VERSION 5.4 ;
NAMESCASESENSITIVE ON ;
BUSBITCHARS "[]" ;
DIVIDERCHAR "/" ;
UNITS
  DATABASE MICRONS 2000 ;
END UNITS
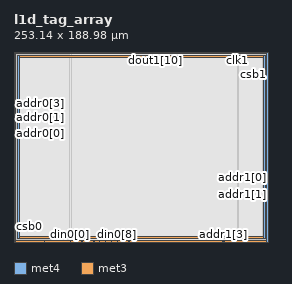
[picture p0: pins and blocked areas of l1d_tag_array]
MACRO l1d_tag_array
   CLASS BLOCK ;
   SIZE 253.14 BY 188.98 ;
   SYMMETRY X Y R90 ;
   PIN din0[0]
      DIRECTION INPUT ;
      PORT
         LAYER met4 ;
         RECT  55.92 0.0 56.3 0.38 ;
      END
   END din0[0]
   PIN din0[1]
      DIRECTION INPUT ;
      PORT
         LAYER met4 ;
         RECT  61.76 0.0 62.14 0.38 ;
      END
   END din0[1]
   PIN din0[2]
      DIRECTION INPUT ;
      PORT
         LAYER met4 ;
         RECT  67.6 0.0 67.98 0.38 ;
      END
   END din0[2]
   PIN din0[3]
      DIRECTION INPUT ;
      PORT
         LAYER met4 ;
         RECT  73.44 0.0 73.82 0.38 ;
      END
   END din0[3]
   PIN din0[4]
      DIRECTION INPUT ;
      PORT
         LAYER met4 ;
         RECT  79.28 0.0 79.66 0.38 ;
      END
   END din0[4]
   PIN din0[5]
      DIRECTION INPUT ;
      PORT
         LAYER met4 ;
         RECT  85.12 0.0 85.5 0.38 ;
      END
   END din0[5]
   PIN din0[6]
      DIRECTION INPUT ;
      PORT
         LAYER met4 ;
         RECT  90.96 0.0 91.34 0.38 ;
      END
   END din0[6]
   PIN din0[7]
      DIRECTION INPUT ;
      PORT
         LAYER met4 ;
         RECT  96.8 0.0 97.18 0.38 ;
      END
   END din0[7]
   PIN din0[8]
      DIRECTION INPUT ;
      PORT
         LAYER met4 ;
         RECT  102.64 0.0 103.02 0.38 ;
      END
   END din0[8]
   PIN din0[9]
      DIRECTION INPUT ;
      PORT
         LAYER met4 ;
         RECT  108.48 0.0 108.86 0.38 ;
      END
   END din0[9]
   PIN din0[10]
      DIRECTION INPUT ;
      PORT
         LAYER met4 ;
         RECT  114.32 0.0 114.7 0.38 ;
      END
   END din0[10]
   PIN addr0[0]
      DIRECTION INPUT ;
      PORT
         LAYER met3 ;
         RECT  0.0 107.58 0.38 107.96 ;
      END
   END addr0[0]
   PIN addr0[1]
      DIRECTION INPUT ;
      PORT
         LAYER met3 ;
         RECT  0.0 116.08 0.38 116.46 ;
      END
   END addr0[1]
   PIN addr0[2]
      DIRECTION INPUT ;
      PORT
         LAYER met3 ;
         RECT  0.0 121.72 0.38 122.1 ;
      END
   END addr0[2]
   PIN addr0[3]
      DIRECTION INPUT ;
      PORT
         LAYER met3 ;
         RECT  0.0 130.22 0.38 130.6 ;
      END
   END addr0[3]
   PIN addr0[4]
      DIRECTION INPUT ;
      PORT
         LAYER met3 ;
         RECT  0.0 136.275 0.38 136.655 ;
      END
   END addr0[4]
   PIN addr1[0]
      DIRECTION INPUT ;
      PORT
         LAYER met3 ;
         RECT  252.76 63.54 253.14 63.92 ;
      END
   END addr1[0]
   PIN addr1[1]
      DIRECTION INPUT ;
      PORT
         LAYER met3 ;
         RECT  252.76 55.04 253.14 55.42 ;
      END
   END addr1[1]
   PIN addr1[2]
      DIRECTION INPUT ;
      PORT
         LAYER met3 ;
         RECT  252.76 49.4 253.14 49.78 ;
      END
   END addr1[2]
   PIN addr1[3]
      DIRECTION INPUT ;
      PORT
         LAYER met4 ;
         RECT  207.775 0.0 208.155 0.38 ;
      END
   END addr1[3]
   PIN addr1[4]
      DIRECTION INPUT ;
      PORT
         LAYER met4 ;
         RECT  208.52 0.0 208.9 0.38 ;
      END
   END addr1[4]
   PIN csb0
      DIRECTION INPUT ;
      PORT
         LAYER met3 ;
         RECT  0.0 14.87 0.38 15.25 ;
      END
   END csb0
   PIN csb1
      DIRECTION INPUT ;
      PORT
         LAYER met3 ;
         RECT  252.76 173.73 253.14 174.11 ;
      END
   END csb1
   PIN clk0
      DIRECTION INPUT ;
      PORT
         LAYER met4 ;
         RECT  30.26 0.0 30.64 0.38 ;
      END
   END clk0
   PIN clk1
      DIRECTION INPUT ;
      PORT
         LAYER met4 ;
         RECT  222.5 188.6 222.88 188.98 ;
      END
   END clk1
   PIN dout1[0]
      DIRECTION OUTPUT ;
      PORT
         LAYER met4 ;
         RECT  109.645 188.6 110.025 188.98 ;
      END
   END dout1[0]
   PIN dout1[1]
      DIRECTION OUTPUT ;
      PORT
         LAYER met4 ;
         RECT  114.615 188.6 114.995 188.98 ;
      END
   END dout1[1]
   PIN dout1[2]
      DIRECTION OUTPUT ;
      PORT
         LAYER met4 ;
         RECT  115.885 188.6 116.265 188.98 ;
      END
   END dout1[2]
   PIN dout1[3]
      DIRECTION OUTPUT ;
      PORT
         LAYER met4 ;
         RECT  120.855 188.6 121.235 188.98 ;
      END
   END dout1[3]
   PIN dout1[4]
      DIRECTION OUTPUT ;
      PORT
         LAYER met4 ;
         RECT  122.125 188.6 122.505 188.98 ;
      END
   END dout1[4]
   PIN dout1[5]
      DIRECTION OUTPUT ;
      PORT
         LAYER met4 ;
         RECT  127.095 188.6 127.475 188.98 ;
      END
   END dout1[5]
   PIN dout1[6]
      DIRECTION OUTPUT ;
      PORT
         LAYER met4 ;
         RECT  128.365 188.6 128.745 188.98 ;
      END
   END dout1[6]
   PIN dout1[7]
      DIRECTION OUTPUT ;
      PORT
         LAYER met4 ;
         RECT  133.335 188.6 133.715 188.98 ;
      END
   END dout1[7]
   PIN dout1[8]
      DIRECTION OUTPUT ;
      PORT
         LAYER met4 ;
         RECT  134.605 188.6 134.985 188.98 ;
      END
   END dout1[8]
   PIN dout1[9]
      DIRECTION OUTPUT ;
      PORT
         LAYER met4 ;
         RECT  139.575 188.6 139.955 188.98 ;
      END
   END dout1[9]
   PIN dout1[10]
      DIRECTION OUTPUT ;
      PORT
         LAYER met4 ;
         RECT  140.845 188.6 141.225 188.98 ;
      END
   END dout1[10]
   PIN vccd1
      DIRECTION INOUT ;
      USE POWER ; 
      SHAPE ABUTMENT ; 
      PORT
         LAYER met3 ;
         RECT  0.0 187.24 253.14 188.98 ;
         LAYER met3 ;
         RECT  0.0 0.0 253.14 1.74 ;
         LAYER met4 ;
         RECT  251.4 0.0 253.14 188.98 ;
         LAYER met4 ;
         RECT  0.0 0.0 1.74 188.98 ;
      END
   END vccd1
   PIN vssd1
      DIRECTION INOUT ;
      USE GROUND ; 
      SHAPE ABUTMENT ; 
      PORT
         LAYER met3 ;
         RECT  3.48 183.76 249.66 185.5 ;
         LAYER met3 ;
         RECT  3.48 3.48 249.66 5.22 ;
         LAYER met4 ;
         RECT  3.48 3.48 5.22 185.5 ;
         LAYER met4 ;
         RECT  247.92 3.48 249.66 185.5 ;
      END
   END vssd1
   OBS
   LAYER  met1 ;
      RECT  0.62 0.62 252.52 188.36 ;
   LAYER  met2 ;
      RECT  0.62 0.62 252.52 188.36 ;
   LAYER  met3 ;
      RECT  0.98 106.98 252.52 108.56 ;
      RECT  0.62 108.56 0.98 115.48 ;
      RECT  0.62 117.06 0.98 121.12 ;
      RECT  0.62 122.7 0.98 129.62 ;
      RECT  0.62 131.2 0.98 135.675 ;
      RECT  0.98 62.94 252.16 64.52 ;
      RECT  0.98 64.52 252.16 106.98 ;
      RECT  252.16 64.52 252.52 106.98 ;
      RECT  252.16 56.02 252.52 62.94 ;
      RECT  252.16 50.38 252.52 54.44 ;
      RECT  0.62 15.85 0.98 106.98 ;
      RECT  0.98 108.56 252.16 173.13 ;
      RECT  0.98 173.13 252.16 174.71 ;
      RECT  252.16 108.56 252.52 173.13 ;
      RECT  0.62 137.255 0.98 186.64 ;
      RECT  252.16 174.71 252.52 186.64 ;
      RECT  252.16 2.34 252.52 48.8 ;
      RECT  0.62 2.34 0.98 14.27 ;
      RECT  0.98 174.71 2.88 183.16 ;
      RECT  0.98 183.16 2.88 186.1 ;
      RECT  0.98 186.1 2.88 186.64 ;
      RECT  2.88 174.71 250.26 183.16 ;
      RECT  2.88 186.1 250.26 186.64 ;
      RECT  250.26 174.71 252.16 183.16 ;
      RECT  250.26 183.16 252.16 186.1 ;
      RECT  250.26 186.1 252.16 186.64 ;
      RECT  0.98 2.34 2.88 2.88 ;
      RECT  0.98 2.88 2.88 5.82 ;
      RECT  0.98 5.82 2.88 62.94 ;
      RECT  2.88 2.34 250.26 2.88 ;
      RECT  2.88 5.82 250.26 62.94 ;
      RECT  250.26 2.34 252.16 2.88 ;
      RECT  250.26 2.88 252.16 5.82 ;
      RECT  250.26 5.82 252.16 62.94 ;
   LAYER  met4 ;
      RECT  55.32 0.98 56.9 188.36 ;
      RECT  56.9 0.62 61.16 0.98 ;
      RECT  62.74 0.62 67.0 0.98 ;
      RECT  68.58 0.62 72.84 0.98 ;
      RECT  74.42 0.62 78.68 0.98 ;
      RECT  80.26 0.62 84.52 0.98 ;
      RECT  86.1 0.62 90.36 0.98 ;
      RECT  91.94 0.62 96.2 0.98 ;
      RECT  97.78 0.62 102.04 0.98 ;
      RECT  103.62 0.62 107.88 0.98 ;
      RECT  109.46 0.62 113.72 0.98 ;
      RECT  115.3 0.62 207.175 0.98 ;
      RECT  31.24 0.62 55.32 0.98 ;
      RECT  56.9 0.98 221.9 188.0 ;
      RECT  221.9 0.98 223.48 188.0 ;
      RECT  56.9 188.0 109.045 188.36 ;
      RECT  110.625 188.0 114.015 188.36 ;
      RECT  116.865 188.0 120.255 188.36 ;
      RECT  123.105 188.0 126.495 188.36 ;
      RECT  129.345 188.0 132.735 188.36 ;
      RECT  135.585 188.0 138.975 188.36 ;
      RECT  141.825 188.0 221.9 188.36 ;
      RECT  209.5 0.62 250.8 0.98 ;
      RECT  223.48 188.0 250.8 188.36 ;
      RECT  2.34 0.62 29.66 0.98 ;
      RECT  2.34 0.98 2.88 2.88 ;
      RECT  2.34 2.88 2.88 186.1 ;
      RECT  2.34 186.1 2.88 188.36 ;
      RECT  2.88 0.98 5.82 2.88 ;
      RECT  2.88 186.1 5.82 188.36 ;
      RECT  5.82 0.98 55.32 2.88 ;
      RECT  5.82 2.88 55.32 186.1 ;
      RECT  5.82 186.1 55.32 188.36 ;
      RECT  223.48 0.98 247.32 2.88 ;
      RECT  223.48 2.88 247.32 186.1 ;
      RECT  223.48 186.1 247.32 188.0 ;
      RECT  247.32 0.98 250.26 2.88 ;
      RECT  247.32 186.1 250.26 188.0 ;
      RECT  250.26 0.98 250.8 2.88 ;
      RECT  250.26 2.88 250.8 186.1 ;
      RECT  250.26 186.1 250.8 188.0 ;
   END
END    l1d_tag_array
END    LIBRARY
